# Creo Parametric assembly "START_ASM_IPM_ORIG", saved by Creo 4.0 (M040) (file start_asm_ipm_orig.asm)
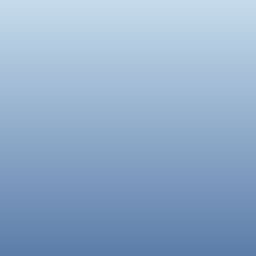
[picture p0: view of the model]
Units: IPM (mmkgsecC); MM, KILOGRAM, SECS

Other parameters: HMOTNOST

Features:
  1. datum plane "ASM_BOKORYS"
  2. datum plane "ASM_PODORYS"
  3. datum plane "ASM_NARYS"
  4. coordinate system

Other named items: ASM_KSYS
